One B-rep face of a CAD part: STEP entity #2398.
In plain terms, the planar face has unit normal (1, 0, 0).
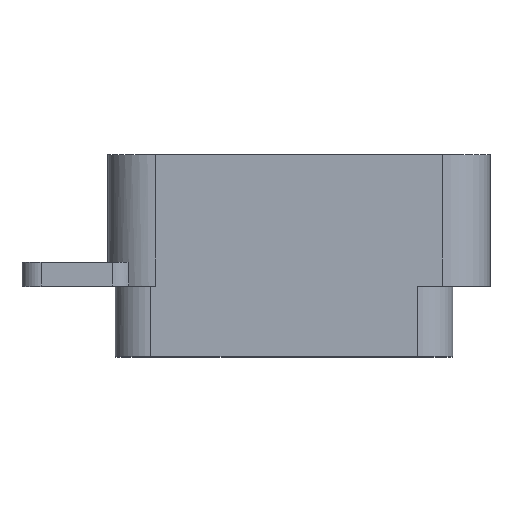
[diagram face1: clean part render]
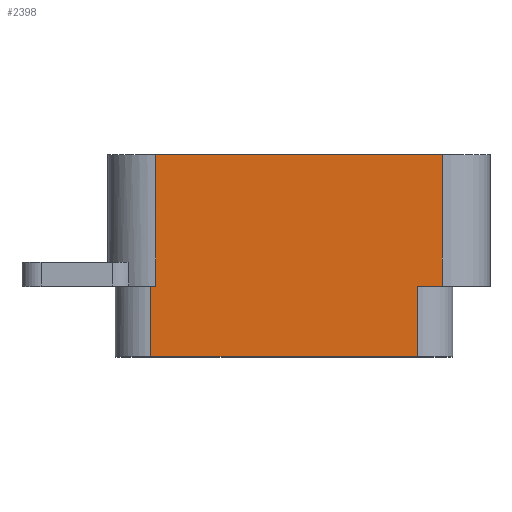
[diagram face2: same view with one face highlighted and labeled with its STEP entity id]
Its self-contained STEP definition (entity closure, numbers rounded to 3 decimals):
#547 = PLANE('',#548);
#548 = AXIS2_PLACEMENT_3D('',#549,#550,#551);
#549 = CARTESIAN_POINT('',(44.7,-1.3,10.));
#550 = DIRECTION('',(0.,-1.,0.));
#551 = DIRECTION('',(1.,0.,0.));
#1234 = PLANE('',#1235);
#1235 = AXIS2_PLACEMENT_3D('',#1236,#1237,#1238);
#1236 = CARTESIAN_POINT('',(44.7,4.2,10.));
#1237 = DIRECTION('',(0.,-1.,0.));
#1238 = DIRECTION('',(1.,0.,0.));
#1262 = CYLINDRICAL_SURFACE('',#1263,2.);
#1263 = AXIS2_PLACEMENT_3D('',#1264,#1265,#1266);
#1264 = CARTESIAN_POINT('',(51.7,-1.3,4.));
#1265 = DIRECTION('',(0.,-1.,0.));
#1266 = DIRECTION('',(1.,0.,0.));
#1371 = VERTEX_POINT('',#1372);
#1372 = CARTESIAN_POINT('',(53.7,-1.3,4.));
#1394 = EDGE_CURVE('',#1371,#1395,#1397,.T.);
#1395 = VERTEX_POINT('',#1396);
#1396 = CARTESIAN_POINT('',(53.7,-1.3,5.05));
#1397 = SURFACE_CURVE('',#1398,(#1402,#1409),.PCURVE_S1.);
#1398 = LINE('',#1399,#1400);
#1399 = CARTESIAN_POINT('',(53.7,-1.3,10.));
#1400 = VECTOR('',#1401,1.);
#1401 = DIRECTION('',(0.,0.,1.));
#1402 = PCURVE('',#547,#1403);
#1403 = DEFINITIONAL_REPRESENTATION('',(#1404),#1408);
#1404 = LINE('',#1405,#1406);
#1405 = CARTESIAN_POINT('',(9.,0.));
#1406 = VECTOR('',#1407,1.);
#1407 = DIRECTION('',(0.,1.));
#1408 = ( GEOMETRIC_REPRESENTATION_CONTEXT(2) 
PARAMETRIC_REPRESENTATION_CONTEXT() REPRESENTATION_CONTEXT('2D SPACE',''
  ) );
#1409 = PCURVE('',#1410,#1415);
#1410 = PLANE('',#1411);
#1411 = AXIS2_PLACEMENT_3D('',#1412,#1413,#1414);
#1412 = CARTESIAN_POINT('',(53.7,-1.3,4.));
#1413 = DIRECTION('',(1.,0.,-0.));
#1414 = DIRECTION('',(0.,0.,1.));
#1415 = DEFINITIONAL_REPRESENTATION('',(#1416),#1420);
#1416 = LINE('',#1417,#1418);
#1417 = CARTESIAN_POINT('',(6.,0.));
#1418 = VECTOR('',#1419,1.);
#1419 = DIRECTION('',(1.,0.));
#1420 = ( GEOMETRIC_REPRESENTATION_CONTEXT(2) 
PARAMETRIC_REPRESENTATION_CONTEXT() REPRESENTATION_CONTEXT('2D SPACE',''
  ) );
#1439 = CYLINDRICAL_SURFACE('',#1440,1.5);
#1440 = AXIS2_PLACEMENT_3D('',#1441,#1442,#1443);
#1441 = CARTESIAN_POINT('',(52.2,-4.25,5.05));
#1442 = DIRECTION('',(0.,-1.,0.));
#1443 = DIRECTION('',(1.,0.,0.));
#1594 = PLANE('',#1595);
#1595 = AXIS2_PLACEMENT_3D('',#1596,#1597,#1598);
#1596 = CARTESIAN_POINT('',(44.7,-4.25,10.625));
#1597 = DIRECTION('',(0.,-1.,0.));
#1598 = DIRECTION('',(1.,0.,0.));
#2115 = VERTEX_POINT('',#2116);
#2116 = CARTESIAN_POINT('',(53.7,4.2,4.));
#2138 = EDGE_CURVE('',#1371,#2115,#2139,.T.);
#2139 = SURFACE_CURVE('',#2140,(#2144,#2151),.PCURVE_S1.);
#2140 = LINE('',#2141,#2142);
#2141 = CARTESIAN_POINT('',(53.7,-1.3,4.));
#2142 = VECTOR('',#2143,1.);
#2143 = DIRECTION('',(-0.,1.,-0.));
#2144 = PCURVE('',#1262,#2145);
#2145 = DEFINITIONAL_REPRESENTATION('',(#2146),#2150);
#2146 = LINE('',#2147,#2148);
#2147 = CARTESIAN_POINT('',(6.283,0.));
#2148 = VECTOR('',#2149,1.);
#2149 = DIRECTION('',(0.,-1.));
#2150 = ( GEOMETRIC_REPRESENTATION_CONTEXT(2) 
PARAMETRIC_REPRESENTATION_CONTEXT() REPRESENTATION_CONTEXT('2D SPACE',''
  ) );
#2151 = PCURVE('',#1410,#2152);
#2152 = DEFINITIONAL_REPRESENTATION('',(#2153),#2157);
#2153 = LINE('',#2154,#2155);
#2154 = CARTESIAN_POINT('',(0.,0.));
#2155 = VECTOR('',#2156,1.);
#2156 = DIRECTION('',(0.,-1.));
#2157 = ( GEOMETRIC_REPRESENTATION_CONTEXT(2) 
PARAMETRIC_REPRESENTATION_CONTEXT() REPRESENTATION_CONTEXT('2D SPACE',''
  ) );
#2212 = EDGE_CURVE('',#2115,#2213,#2215,.T.);
#2213 = VERTEX_POINT('',#2214);
#2214 = CARTESIAN_POINT('',(53.7,4.2,16.));
#2215 = SURFACE_CURVE('',#2216,(#2220,#2227),.PCURVE_S1.);
#2216 = LINE('',#2217,#2218);
#2217 = CARTESIAN_POINT('',(53.7,4.2,10.));
#2218 = VECTOR('',#2219,1.);
#2219 = DIRECTION('',(0.,0.,1.));
#2220 = PCURVE('',#1234,#2221);
#2221 = DEFINITIONAL_REPRESENTATION('',(#2222),#2226);
#2222 = LINE('',#2223,#2224);
#2223 = CARTESIAN_POINT('',(9.,0.));
#2224 = VECTOR('',#2225,1.);
#2225 = DIRECTION('',(0.,1.));
#2226 = ( GEOMETRIC_REPRESENTATION_CONTEXT(2) 
PARAMETRIC_REPRESENTATION_CONTEXT() REPRESENTATION_CONTEXT('2D SPACE',''
  ) );
#2227 = PCURVE('',#1410,#2228);
#2228 = DEFINITIONAL_REPRESENTATION('',(#2229),#2233);
#2229 = LINE('',#2230,#2231);
#2230 = CARTESIAN_POINT('',(6.,-5.5));
#2231 = VECTOR('',#2232,1.);
#2232 = DIRECTION('',(1.,0.));
#2233 = ( GEOMETRIC_REPRESENTATION_CONTEXT(2) 
PARAMETRIC_REPRESENTATION_CONTEXT() REPRESENTATION_CONTEXT('2D SPACE',''
  ) );
#2252 = CYLINDRICAL_SURFACE('',#2253,2.);
#2253 = AXIS2_PLACEMENT_3D('',#2254,#2255,#2256);
#2254 = CARTESIAN_POINT('',(51.7,-1.3,16.));
#2255 = DIRECTION('',(0.,-1.,0.));
#2256 = DIRECTION('',(1.,0.,0.));
#2354 = EDGE_CURVE('',#2355,#1395,#2357,.T.);
#2355 = VERTEX_POINT('',#2356);
#2356 = CARTESIAN_POINT('',(53.7,-4.25,5.05));
#2357 = SURFACE_CURVE('',#2358,(#2362,#2369),.PCURVE_S1.);
#2358 = LINE('',#2359,#2360);
#2359 = CARTESIAN_POINT('',(53.7,-4.25,5.05));
#2360 = VECTOR('',#2361,1.);
#2361 = DIRECTION('',(-0.,1.,-0.));
#2362 = PCURVE('',#1439,#2363);
#2363 = DEFINITIONAL_REPRESENTATION('',(#2364),#2368);
#2364 = LINE('',#2365,#2366);
#2365 = CARTESIAN_POINT('',(6.283,0.));
#2366 = VECTOR('',#2367,1.);
#2367 = DIRECTION('',(0.,-1.));
#2368 = ( GEOMETRIC_REPRESENTATION_CONTEXT(2) 
PARAMETRIC_REPRESENTATION_CONTEXT() REPRESENTATION_CONTEXT('2D SPACE',''
  ) );
#2369 = PCURVE('',#1410,#2370);
#2370 = DEFINITIONAL_REPRESENTATION('',(#2371),#2375);
#2371 = LINE('',#2372,#2373);
#2372 = CARTESIAN_POINT('',(1.05,2.95));
#2373 = VECTOR('',#2374,1.);
#2374 = DIRECTION('',(0.,-1.));
#2375 = ( GEOMETRIC_REPRESENTATION_CONTEXT(2) 
PARAMETRIC_REPRESENTATION_CONTEXT() REPRESENTATION_CONTEXT('2D SPACE',''
  ) );
#2398 = ADVANCED_FACE('',(#2399),#1410,.T.);
#2399 = FACE_BOUND('',#2400,.T.);
#2400 = EDGE_LOOP('',(#2401,#2402,#2403,#2426,#2454,#2482,#2503,#2504));
#2401 = ORIENTED_EDGE('',*,*,#2138,.T.);
#2402 = ORIENTED_EDGE('',*,*,#2212,.T.);
#2403 = ORIENTED_EDGE('',*,*,#2404,.F.);
#2404 = EDGE_CURVE('',#2405,#2213,#2407,.T.);
#2405 = VERTEX_POINT('',#2406);
#2406 = CARTESIAN_POINT('',(53.7,-1.3,16.));
#2407 = SURFACE_CURVE('',#2408,(#2412,#2419),.PCURVE_S1.);
#2408 = LINE('',#2409,#2410);
#2409 = CARTESIAN_POINT('',(53.7,-1.3,16.));
#2410 = VECTOR('',#2411,1.);
#2411 = DIRECTION('',(-0.,1.,-0.));
#2412 = PCURVE('',#1410,#2413);
#2413 = DEFINITIONAL_REPRESENTATION('',(#2414),#2418);
#2414 = LINE('',#2415,#2416);
#2415 = CARTESIAN_POINT('',(12.,0.));
#2416 = VECTOR('',#2417,1.);
#2417 = DIRECTION('',(0.,-1.));
#2418 = ( GEOMETRIC_REPRESENTATION_CONTEXT(2) 
PARAMETRIC_REPRESENTATION_CONTEXT() REPRESENTATION_CONTEXT('2D SPACE',''
  ) );
#2419 = PCURVE('',#2252,#2420);
#2420 = DEFINITIONAL_REPRESENTATION('',(#2421),#2425);
#2421 = LINE('',#2422,#2423);
#2422 = CARTESIAN_POINT('',(0.,0.));
#2423 = VECTOR('',#2424,1.);
#2424 = DIRECTION('',(0.,-1.));
#2425 = ( GEOMETRIC_REPRESENTATION_CONTEXT(2) 
PARAMETRIC_REPRESENTATION_CONTEXT() REPRESENTATION_CONTEXT('2D SPACE',''
  ) );
#2426 = ORIENTED_EDGE('',*,*,#2427,.T.);
#2427 = EDGE_CURVE('',#2405,#2428,#2430,.T.);
#2428 = VERTEX_POINT('',#2429);
#2429 = CARTESIAN_POINT('',(53.7,-1.3,16.2));
#2430 = SURFACE_CURVE('',#2431,(#2435,#2442),.PCURVE_S1.);
#2431 = LINE('',#2432,#2433);
#2432 = CARTESIAN_POINT('',(53.7,-1.3,10.625));
#2433 = VECTOR('',#2434,1.);
#2434 = DIRECTION('',(0.,0.,1.));
#2435 = PCURVE('',#1410,#2436);
#2436 = DEFINITIONAL_REPRESENTATION('',(#2437),#2441);
#2437 = LINE('',#2438,#2439);
#2438 = CARTESIAN_POINT('',(6.625,0.));
#2439 = VECTOR('',#2440,1.);
#2440 = DIRECTION('',(1.,0.));
#2441 = ( GEOMETRIC_REPRESENTATION_CONTEXT(2) 
PARAMETRIC_REPRESENTATION_CONTEXT() REPRESENTATION_CONTEXT('2D SPACE',''
  ) );
#2442 = PCURVE('',#2443,#2448);
#2443 = PLANE('',#2444);
#2444 = AXIS2_PLACEMENT_3D('',#2445,#2446,#2447);
#2445 = CARTESIAN_POINT('',(44.7,-1.3,10.625));
#2446 = DIRECTION('',(0.,-1.,0.));
#2447 = DIRECTION('',(1.,0.,0.));
#2448 = DEFINITIONAL_REPRESENTATION('',(#2449),#2453);
#2449 = LINE('',#2450,#2451);
#2450 = CARTESIAN_POINT('',(9.,0.));
#2451 = VECTOR('',#2452,1.);
#2452 = DIRECTION('',(0.,1.));
#2453 = ( GEOMETRIC_REPRESENTATION_CONTEXT(2) 
PARAMETRIC_REPRESENTATION_CONTEXT() REPRESENTATION_CONTEXT('2D SPACE',''
  ) );
#2454 = ORIENTED_EDGE('',*,*,#2455,.F.);
#2455 = EDGE_CURVE('',#2456,#2428,#2458,.T.);
#2456 = VERTEX_POINT('',#2457);
#2457 = CARTESIAN_POINT('',(53.7,-4.25,16.2));
#2458 = SURFACE_CURVE('',#2459,(#2463,#2470),.PCURVE_S1.);
#2459 = LINE('',#2460,#2461);
#2460 = CARTESIAN_POINT('',(53.7,-4.25,16.2));
#2461 = VECTOR('',#2462,1.);
#2462 = DIRECTION('',(-0.,1.,-0.));
#2463 = PCURVE('',#1410,#2464);
#2464 = DEFINITIONAL_REPRESENTATION('',(#2465),#2469);
#2465 = LINE('',#2466,#2467);
#2466 = CARTESIAN_POINT('',(12.2,2.95));
#2467 = VECTOR('',#2468,1.);
#2468 = DIRECTION('',(0.,-1.));
#2469 = ( GEOMETRIC_REPRESENTATION_CONTEXT(2) 
PARAMETRIC_REPRESENTATION_CONTEXT() REPRESENTATION_CONTEXT('2D SPACE',''
  ) );
#2470 = PCURVE('',#2471,#2476);
#2471 = CYLINDRICAL_SURFACE('',#2472,1.5);
#2472 = AXIS2_PLACEMENT_3D('',#2473,#2474,#2475);
#2473 = CARTESIAN_POINT('',(52.2,-4.25,16.2));
#2474 = DIRECTION('',(0.,-1.,0.));
#2475 = DIRECTION('',(1.,0.,0.));
#2476 = DEFINITIONAL_REPRESENTATION('',(#2477),#2481);
#2477 = LINE('',#2478,#2479);
#2478 = CARTESIAN_POINT('',(0.,0.));
#2479 = VECTOR('',#2480,1.);
#2480 = DIRECTION('',(0.,-1.));
#2481 = ( GEOMETRIC_REPRESENTATION_CONTEXT(2) 
PARAMETRIC_REPRESENTATION_CONTEXT() REPRESENTATION_CONTEXT('2D SPACE',''
  ) );
#2482 = ORIENTED_EDGE('',*,*,#2483,.F.);
#2483 = EDGE_CURVE('',#2355,#2456,#2484,.T.);
#2484 = SURFACE_CURVE('',#2485,(#2489,#2496),.PCURVE_S1.);
#2485 = LINE('',#2486,#2487);
#2486 = CARTESIAN_POINT('',(53.7,-4.25,10.625));
#2487 = VECTOR('',#2488,1.);
#2488 = DIRECTION('',(0.,0.,1.));
#2489 = PCURVE('',#1410,#2490);
#2490 = DEFINITIONAL_REPRESENTATION('',(#2491),#2495);
#2491 = LINE('',#2492,#2493);
#2492 = CARTESIAN_POINT('',(6.625,2.95));
#2493 = VECTOR('',#2494,1.);
#2494 = DIRECTION('',(1.,0.));
#2495 = ( GEOMETRIC_REPRESENTATION_CONTEXT(2) 
PARAMETRIC_REPRESENTATION_CONTEXT() REPRESENTATION_CONTEXT('2D SPACE',''
  ) );
#2496 = PCURVE('',#1594,#2497);
#2497 = DEFINITIONAL_REPRESENTATION('',(#2498),#2502);
#2498 = LINE('',#2499,#2500);
#2499 = CARTESIAN_POINT('',(9.,0.));
#2500 = VECTOR('',#2501,1.);
#2501 = DIRECTION('',(0.,1.));
#2502 = ( GEOMETRIC_REPRESENTATION_CONTEXT(2) 
PARAMETRIC_REPRESENTATION_CONTEXT() REPRESENTATION_CONTEXT('2D SPACE',''
  ) );
#2503 = ORIENTED_EDGE('',*,*,#2354,.T.);
#2504 = ORIENTED_EDGE('',*,*,#1394,.F.);
